# Generated by OpenFakeRAM
VERSION 5.7 ;
BUSBITCHARS "[]" ;
PROPERTYDEFINITIONS
  MACRO width INTEGER ;
  MACRO depth INTEGER ;
  MACRO banks INTEGER ;
END PROPERTYDEFINITIONS
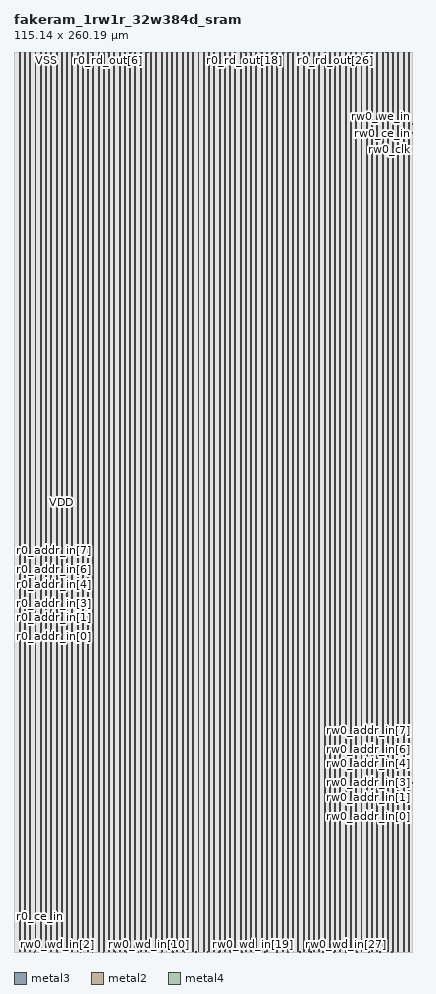
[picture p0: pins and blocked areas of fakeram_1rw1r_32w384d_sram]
MACRO fakeram_1rw1r_32w384d_sram
  PROPERTY width 32 ;
  PROPERTY depth 384 ;
  PROPERTY banks 1 ;
  FOREIGN fakeram_1rw1r_32w384d_sram 0 0 ;
  SYMMETRY X Y R90 ;
  SIZE 115.140 BY 260.190 ;
  CLASS BLOCK ;
  PIN r0_clk
    DIRECTION INPUT ;
    USE SIGNAL ;
    SHAPE ABUTMENT ;
    PORT
      LAYER metal3 ;
      RECT 0.000 7.945 0.070 8.015 ;
    END
  END r0_clk
  PIN r0_ce_in
    DIRECTION INPUT ;
    USE SIGNAL ;
    SHAPE ABUTMENT ;
    PORT
      LAYER metal3 ;
      RECT 0.000 10.325 0.070 10.395 ;
    END
  END r0_ce_in
  PIN r0_addr_in[0]
    DIRECTION INPUT ;
    USE SIGNAL ;
    SHAPE ABUTMENT ;
    PORT
      LAYER metal3 ;
      RECT 0.000 91.105 0.070 91.175 ;
    END
  END r0_addr_in[0]
  PIN r0_addr_in[1]
    DIRECTION INPUT ;
    USE SIGNAL ;
    SHAPE ABUTMENT ;
    PORT
      LAYER metal3 ;
      RECT 0.000 94.325 0.070 94.395 ;
    END
  END r0_addr_in[1]
  PIN r0_addr_in[2]
    DIRECTION INPUT ;
    USE SIGNAL ;
    SHAPE ABUTMENT ;
    PORT
      LAYER metal3 ;
      RECT 0.000 97.545 0.070 97.615 ;
    END
  END r0_addr_in[2]
  PIN r0_addr_in[3]
    DIRECTION INPUT ;
    USE SIGNAL ;
    SHAPE ABUTMENT ;
    PORT
      LAYER metal3 ;
      RECT 0.000 100.765 0.070 100.835 ;
    END
  END r0_addr_in[3]
  PIN r0_addr_in[4]
    DIRECTION INPUT ;
    USE SIGNAL ;
    SHAPE ABUTMENT ;
    PORT
      LAYER metal3 ;
      RECT 0.000 103.985 0.070 104.055 ;
    END
  END r0_addr_in[4]
  PIN r0_addr_in[5]
    DIRECTION INPUT ;
    USE SIGNAL ;
    SHAPE ABUTMENT ;
    PORT
      LAYER metal3 ;
      RECT 0.000 107.345 0.070 107.415 ;
    END
  END r0_addr_in[5]
  PIN r0_addr_in[6]
    DIRECTION INPUT ;
    USE SIGNAL ;
    SHAPE ABUTMENT ;
    PORT
      LAYER metal3 ;
      RECT 0.000 110.565 0.070 110.635 ;
    END
  END r0_addr_in[6]
  PIN r0_addr_in[7]
    DIRECTION INPUT ;
    USE SIGNAL ;
    SHAPE ABUTMENT ;
    PORT
      LAYER metal3 ;
      RECT 0.000 113.785 0.070 113.855 ;
    END
  END r0_addr_in[7]
  PIN r0_addr_in[8]
    DIRECTION INPUT ;
    USE SIGNAL ;
    SHAPE ABUTMENT ;
    PORT
      LAYER metal3 ;
      RECT 0.000 117.005 0.070 117.075 ;
    END
  END r0_addr_in[8]
  PIN rw0_rd_out[0]
    DIRECTION OUTPUT ;
    USE SIGNAL ;
    SHAPE ABUTMENT ;
    PORT
      LAYER metal2 ;
      RECT 5.855 260.120 5.925 260.190 ;
    END
  END rw0_rd_out[0]
  PIN r0_rd_out[0]
    DIRECTION OUTPUT ;
    USE SIGNAL ;
    SHAPE ABUTMENT ;
    PORT
      LAYER metal2 ;
      RECT 7.565 260.120 7.635 260.190 ;
    END
  END r0_rd_out[0]
  PIN rw0_rd_out[1]
    DIRECTION OUTPUT ;
    USE SIGNAL ;
    SHAPE ABUTMENT ;
    PORT
      LAYER metal2 ;
      RECT 9.085 260.120 9.155 260.190 ;
    END
  END rw0_rd_out[1]
  PIN r0_rd_out[1]
    DIRECTION OUTPUT ;
    USE SIGNAL ;
    SHAPE ABUTMENT ;
    PORT
      LAYER metal2 ;
      RECT 10.795 260.120 10.865 260.190 ;
    END
  END r0_rd_out[1]
  PIN rw0_rd_out[2]
    DIRECTION OUTPUT ;
    USE SIGNAL ;
    SHAPE ABUTMENT ;
    PORT
      LAYER metal2 ;
      RECT 12.505 260.120 12.575 260.190 ;
    END
  END rw0_rd_out[2]
  PIN r0_rd_out[2]
    DIRECTION OUTPUT ;
    USE SIGNAL ;
    SHAPE ABUTMENT ;
    PORT
      LAYER metal2 ;
      RECT 14.025 260.120 14.095 260.190 ;
    END
  END r0_rd_out[2]
  PIN rw0_rd_out[3]
    DIRECTION OUTPUT ;
    USE SIGNAL ;
    SHAPE ABUTMENT ;
    PORT
      LAYER metal2 ;
      RECT 15.735 260.120 15.805 260.190 ;
    END
  END rw0_rd_out[3]
  PIN r0_rd_out[3]
    DIRECTION OUTPUT ;
    USE SIGNAL ;
    SHAPE ABUTMENT ;
    PORT
      LAYER metal2 ;
      RECT 17.255 260.120 17.325 260.190 ;
    END
  END r0_rd_out[3]
  PIN rw0_rd_out[4]
    DIRECTION OUTPUT ;
    USE SIGNAL ;
    SHAPE ABUTMENT ;
    PORT
      LAYER metal2 ;
      RECT 18.965 260.120 19.035 260.190 ;
    END
  END rw0_rd_out[4]
  PIN r0_rd_out[4]
    DIRECTION OUTPUT ;
    USE SIGNAL ;
    SHAPE ABUTMENT ;
    PORT
      LAYER metal2 ;
      RECT 20.675 260.120 20.745 260.190 ;
    END
  END r0_rd_out[4]
  PIN rw0_rd_out[5]
    DIRECTION OUTPUT ;
    USE SIGNAL ;
    SHAPE ABUTMENT ;
    PORT
      LAYER metal2 ;
      RECT 22.195 260.120 22.265 260.190 ;
    END
  END rw0_rd_out[5]
  PIN r0_rd_out[5]
    DIRECTION OUTPUT ;
    USE SIGNAL ;
    SHAPE ABUTMENT ;
    PORT
      LAYER metal2 ;
      RECT 23.905 260.120 23.975 260.190 ;
    END
  END r0_rd_out[5]
  PIN rw0_rd_out[6]
    DIRECTION OUTPUT ;
    USE SIGNAL ;
    SHAPE ABUTMENT ;
    PORT
      LAYER metal2 ;
      RECT 25.615 260.120 25.685 260.190 ;
    END
  END rw0_rd_out[6]
  PIN r0_rd_out[6]
    DIRECTION OUTPUT ;
    USE SIGNAL ;
    SHAPE ABUTMENT ;
    PORT
      LAYER metal2 ;
      RECT 27.135 260.120 27.205 260.190 ;
    END
  END r0_rd_out[6]
  PIN rw0_rd_out[7]
    DIRECTION OUTPUT ;
    USE SIGNAL ;
    SHAPE ABUTMENT ;
    PORT
      LAYER metal2 ;
      RECT 28.845 260.120 28.915 260.190 ;
    END
  END rw0_rd_out[7]
  PIN r0_rd_out[7]
    DIRECTION OUTPUT ;
    USE SIGNAL ;
    SHAPE ABUTMENT ;
    PORT
      LAYER metal2 ;
      RECT 30.555 260.120 30.625 260.190 ;
    END
  END r0_rd_out[7]
  PIN rw0_rd_out[8]
    DIRECTION OUTPUT ;
    USE SIGNAL ;
    SHAPE ABUTMENT ;
    PORT
      LAYER metal2 ;
      RECT 32.075 260.120 32.145 260.190 ;
    END
  END rw0_rd_out[8]
  PIN r0_rd_out[8]
    DIRECTION OUTPUT ;
    USE SIGNAL ;
    SHAPE ABUTMENT ;
    PORT
      LAYER metal2 ;
      RECT 33.785 260.120 33.855 260.190 ;
    END
  END r0_rd_out[8]
  PIN rw0_rd_out[9]
    DIRECTION OUTPUT ;
    USE SIGNAL ;
    SHAPE ABUTMENT ;
    PORT
      LAYER metal2 ;
      RECT 35.305 260.120 35.375 260.190 ;
    END
  END rw0_rd_out[9]
  PIN r0_rd_out[9]
    DIRECTION OUTPUT ;
    USE SIGNAL ;
    SHAPE ABUTMENT ;
    PORT
      LAYER metal2 ;
      RECT 37.015 260.120 37.085 260.190 ;
    END
  END r0_rd_out[9]
  PIN rw0_rd_out[10]
    DIRECTION OUTPUT ;
    USE SIGNAL ;
    SHAPE ABUTMENT ;
    PORT
      LAYER metal2 ;
      RECT 38.725 260.120 38.795 260.190 ;
    END
  END rw0_rd_out[10]
  PIN r0_rd_out[10]
    DIRECTION OUTPUT ;
    USE SIGNAL ;
    SHAPE ABUTMENT ;
    PORT
      LAYER metal2 ;
      RECT 40.245 260.120 40.315 260.190 ;
    END
  END r0_rd_out[10]
  PIN rw0_rd_out[11]
    DIRECTION OUTPUT ;
    USE SIGNAL ;
    SHAPE ABUTMENT ;
    PORT
      LAYER metal2 ;
      RECT 41.955 260.120 42.025 260.190 ;
    END
  END rw0_rd_out[11]
  PIN r0_rd_out[11]
    DIRECTION OUTPUT ;
    USE SIGNAL ;
    SHAPE ABUTMENT ;
    PORT
      LAYER metal2 ;
      RECT 43.665 260.120 43.735 260.190 ;
    END
  END r0_rd_out[11]
  PIN rw0_rd_out[12]
    DIRECTION OUTPUT ;
    USE SIGNAL ;
    SHAPE ABUTMENT ;
    PORT
      LAYER metal2 ;
      RECT 45.185 260.120 45.255 260.190 ;
    END
  END rw0_rd_out[12]
  PIN r0_rd_out[12]
    DIRECTION OUTPUT ;
    USE SIGNAL ;
    SHAPE ABUTMENT ;
    PORT
      LAYER metal2 ;
      RECT 46.895 260.120 46.965 260.190 ;
    END
  END r0_rd_out[12]
  PIN rw0_rd_out[13]
    DIRECTION OUTPUT ;
    USE SIGNAL ;
    SHAPE ABUTMENT ;
    PORT
      LAYER metal2 ;
      RECT 48.605 260.120 48.675 260.190 ;
    END
  END rw0_rd_out[13]
  PIN r0_rd_out[13]
    DIRECTION OUTPUT ;
    USE SIGNAL ;
    SHAPE ABUTMENT ;
    PORT
      LAYER metal2 ;
      RECT 50.125 260.120 50.195 260.190 ;
    END
  END r0_rd_out[13]
  PIN rw0_rd_out[14]
    DIRECTION OUTPUT ;
    USE SIGNAL ;
    SHAPE ABUTMENT ;
    PORT
      LAYER metal2 ;
      RECT 51.835 260.120 51.905 260.190 ;
    END
  END rw0_rd_out[14]
  PIN r0_rd_out[14]
    DIRECTION OUTPUT ;
    USE SIGNAL ;
    SHAPE ABUTMENT ;
    PORT
      LAYER metal2 ;
      RECT 53.355 260.120 53.425 260.190 ;
    END
  END r0_rd_out[14]
  PIN rw0_rd_out[15]
    DIRECTION OUTPUT ;
    USE SIGNAL ;
    SHAPE ABUTMENT ;
    PORT
      LAYER metal2 ;
      RECT 55.065 260.120 55.135 260.190 ;
    END
  END rw0_rd_out[15]
  PIN r0_rd_out[15]
    DIRECTION OUTPUT ;
    USE SIGNAL ;
    SHAPE ABUTMENT ;
    PORT
      LAYER metal2 ;
      RECT 56.775 260.120 56.845 260.190 ;
    END
  END r0_rd_out[15]
  PIN rw0_rd_out[16]
    DIRECTION OUTPUT ;
    USE SIGNAL ;
    SHAPE ABUTMENT ;
    PORT
      LAYER metal2 ;
      RECT 58.295 260.120 58.365 260.190 ;
    END
  END rw0_rd_out[16]
  PIN r0_rd_out[16]
    DIRECTION OUTPUT ;
    USE SIGNAL ;
    SHAPE ABUTMENT ;
    PORT
      LAYER metal2 ;
      RECT 60.005 260.120 60.075 260.190 ;
    END
  END r0_rd_out[16]
  PIN rw0_rd_out[17]
    DIRECTION OUTPUT ;
    USE SIGNAL ;
    SHAPE ABUTMENT ;
    PORT
      LAYER metal2 ;
      RECT 61.715 260.120 61.785 260.190 ;
    END
  END rw0_rd_out[17]
  PIN r0_rd_out[17]
    DIRECTION OUTPUT ;
    USE SIGNAL ;
    SHAPE ABUTMENT ;
    PORT
      LAYER metal2 ;
      RECT 63.235 260.120 63.305 260.190 ;
    END
  END r0_rd_out[17]
  PIN rw0_rd_out[18]
    DIRECTION OUTPUT ;
    USE SIGNAL ;
    SHAPE ABUTMENT ;
    PORT
      LAYER metal2 ;
      RECT 64.945 260.120 65.015 260.190 ;
    END
  END rw0_rd_out[18]
  PIN r0_rd_out[18]
    DIRECTION OUTPUT ;
    USE SIGNAL ;
    SHAPE ABUTMENT ;
    PORT
      LAYER metal2 ;
      RECT 66.465 260.120 66.535 260.190 ;
    END
  END r0_rd_out[18]
  PIN rw0_rd_out[19]
    DIRECTION OUTPUT ;
    USE SIGNAL ;
    SHAPE ABUTMENT ;
    PORT
      LAYER metal2 ;
      RECT 68.175 260.120 68.245 260.190 ;
    END
  END rw0_rd_out[19]
  PIN r0_rd_out[19]
    DIRECTION OUTPUT ;
    USE SIGNAL ;
    SHAPE ABUTMENT ;
    PORT
      LAYER metal2 ;
      RECT 69.885 260.120 69.955 260.190 ;
    END
  END r0_rd_out[19]
  PIN rw0_rd_out[20]
    DIRECTION OUTPUT ;
    USE SIGNAL ;
    SHAPE ABUTMENT ;
    PORT
      LAYER metal2 ;
      RECT 71.405 260.120 71.475 260.190 ;
    END
  END rw0_rd_out[20]
  PIN r0_rd_out[20]
    DIRECTION OUTPUT ;
    USE SIGNAL ;
    SHAPE ABUTMENT ;
    PORT
      LAYER metal2 ;
      RECT 73.115 260.120 73.185 260.190 ;
    END
  END r0_rd_out[20]
  PIN rw0_rd_out[21]
    DIRECTION OUTPUT ;
    USE SIGNAL ;
    SHAPE ABUTMENT ;
    PORT
      LAYER metal2 ;
      RECT 74.825 260.120 74.895 260.190 ;
    END
  END rw0_rd_out[21]
  PIN r0_rd_out[21]
    DIRECTION OUTPUT ;
    USE SIGNAL ;
    SHAPE ABUTMENT ;
    PORT
      LAYER metal2 ;
      RECT 76.345 260.120 76.415 260.190 ;
    END
  END r0_rd_out[21]
  PIN rw0_rd_out[22]
    DIRECTION OUTPUT ;
    USE SIGNAL ;
    SHAPE ABUTMENT ;
    PORT
      LAYER metal2 ;
      RECT 78.055 260.120 78.125 260.190 ;
    END
  END rw0_rd_out[22]
  PIN r0_rd_out[22]
    DIRECTION OUTPUT ;
    USE SIGNAL ;
    SHAPE ABUTMENT ;
    PORT
      LAYER metal2 ;
      RECT 79.765 260.120 79.835 260.190 ;
    END
  END r0_rd_out[22]
  PIN rw0_rd_out[23]
    DIRECTION OUTPUT ;
    USE SIGNAL ;
    SHAPE ABUTMENT ;
    PORT
      LAYER metal2 ;
      RECT 81.285 260.120 81.355 260.190 ;
    END
  END rw0_rd_out[23]
  PIN r0_rd_out[23]
    DIRECTION OUTPUT ;
    USE SIGNAL ;
    SHAPE ABUTMENT ;
    PORT
      LAYER metal2 ;
      RECT 82.995 260.120 83.065 260.190 ;
    END
  END r0_rd_out[23]
  PIN rw0_rd_out[24]
    DIRECTION OUTPUT ;
    USE SIGNAL ;
    SHAPE ABUTMENT ;
    PORT
      LAYER metal2 ;
      RECT 84.515 260.120 84.585 260.190 ;
    END
  END rw0_rd_out[24]
  PIN r0_rd_out[24]
    DIRECTION OUTPUT ;
    USE SIGNAL ;
    SHAPE ABUTMENT ;
    PORT
      LAYER metal2 ;
      RECT 86.225 260.120 86.295 260.190 ;
    END
  END r0_rd_out[24]
  PIN rw0_rd_out[25]
    DIRECTION OUTPUT ;
    USE SIGNAL ;
    SHAPE ABUTMENT ;
    PORT
      LAYER metal2 ;
      RECT 87.935 260.120 88.005 260.190 ;
    END
  END rw0_rd_out[25]
  PIN r0_rd_out[25]
    DIRECTION OUTPUT ;
    USE SIGNAL ;
    SHAPE ABUTMENT ;
    PORT
      LAYER metal2 ;
      RECT 89.455 260.120 89.525 260.190 ;
    END
  END r0_rd_out[25]
  PIN rw0_rd_out[26]
    DIRECTION OUTPUT ;
    USE SIGNAL ;
    SHAPE ABUTMENT ;
    PORT
      LAYER metal2 ;
      RECT 91.165 260.120 91.235 260.190 ;
    END
  END rw0_rd_out[26]
  PIN r0_rd_out[26]
    DIRECTION OUTPUT ;
    USE SIGNAL ;
    SHAPE ABUTMENT ;
    PORT
      LAYER metal2 ;
      RECT 92.875 260.120 92.945 260.190 ;
    END
  END r0_rd_out[26]
  PIN rw0_rd_out[27]
    DIRECTION OUTPUT ;
    USE SIGNAL ;
    SHAPE ABUTMENT ;
    PORT
      LAYER metal2 ;
      RECT 94.395 260.120 94.465 260.190 ;
    END
  END rw0_rd_out[27]
  PIN r0_rd_out[27]
    DIRECTION OUTPUT ;
    USE SIGNAL ;
    SHAPE ABUTMENT ;
    PORT
      LAYER metal2 ;
      RECT 96.105 260.120 96.175 260.190 ;
    END
  END r0_rd_out[27]
  PIN rw0_rd_out[28]
    DIRECTION OUTPUT ;
    USE SIGNAL ;
    SHAPE ABUTMENT ;
    PORT
      LAYER metal2 ;
      RECT 97.815 260.120 97.885 260.190 ;
    END
  END rw0_rd_out[28]
  PIN r0_rd_out[28]
    DIRECTION OUTPUT ;
    USE SIGNAL ;
    SHAPE ABUTMENT ;
    PORT
      LAYER metal2 ;
      RECT 99.335 260.120 99.405 260.190 ;
    END
  END r0_rd_out[28]
  PIN rw0_rd_out[29]
    DIRECTION OUTPUT ;
    USE SIGNAL ;
    SHAPE ABUTMENT ;
    PORT
      LAYER metal2 ;
      RECT 101.045 260.120 101.115 260.190 ;
    END
  END rw0_rd_out[29]
  PIN r0_rd_out[29]
    DIRECTION OUTPUT ;
    USE SIGNAL ;
    SHAPE ABUTMENT ;
    PORT
      LAYER metal2 ;
      RECT 102.565 260.120 102.635 260.190 ;
    END
  END r0_rd_out[29]
  PIN rw0_rd_out[30]
    DIRECTION OUTPUT ;
    USE SIGNAL ;
    SHAPE ABUTMENT ;
    PORT
      LAYER metal2 ;
      RECT 104.275 260.120 104.345 260.190 ;
    END
  END rw0_rd_out[30]
  PIN r0_rd_out[30]
    DIRECTION OUTPUT ;
    USE SIGNAL ;
    SHAPE ABUTMENT ;
    PORT
      LAYER metal2 ;
      RECT 105.985 260.120 106.055 260.190 ;
    END
  END r0_rd_out[30]
  PIN rw0_rd_out[31]
    DIRECTION OUTPUT ;
    USE SIGNAL ;
    SHAPE ABUTMENT ;
    PORT
      LAYER metal2 ;
      RECT 107.505 260.120 107.575 260.190 ;
    END
  END rw0_rd_out[31]
  PIN r0_rd_out[31]
    DIRECTION OUTPUT ;
    USE SIGNAL ;
    SHAPE ABUTMENT ;
    PORT
      LAYER metal2 ;
      RECT 109.215 260.120 109.285 260.190 ;
    END
  END r0_rd_out[31]
  PIN rw0_clk
    DIRECTION INPUT ;
    USE SIGNAL ;
    SHAPE ABUTMENT ;
    PORT
      LAYER metal3 ;
      RECT 115.070 234.185 115.140 234.255 ;
    END
  END rw0_clk
  PIN rw0_ce_in
    DIRECTION INPUT ;
    USE SIGNAL ;
    SHAPE ABUTMENT ;
    PORT
      LAYER metal3 ;
      RECT 115.070 236.705 115.140 236.775 ;
    END
  END rw0_ce_in
  PIN rw0_we_in
    DIRECTION INPUT ;
    USE SIGNAL ;
    SHAPE ABUTMENT ;
    PORT
      LAYER metal3 ;
      RECT 115.070 239.365 115.140 239.435 ;
    END
  END rw0_we_in
  PIN rw0_addr_in[0]
    DIRECTION INPUT ;
    USE SIGNAL ;
    SHAPE ABUTMENT ;
    PORT
      LAYER metal3 ;
      RECT 115.070 39.165 115.140 39.235 ;
    END
  END rw0_addr_in[0]
  PIN rw0_addr_in[1]
    DIRECTION INPUT ;
    USE SIGNAL ;
    SHAPE ABUTMENT ;
    PORT
      LAYER metal3 ;
      RECT 115.070 42.385 115.140 42.455 ;
    END
  END rw0_addr_in[1]
  PIN rw0_addr_in[2]
    DIRECTION INPUT ;
    USE SIGNAL ;
    SHAPE ABUTMENT ;
    PORT
      LAYER metal3 ;
      RECT 115.070 45.605 115.140 45.675 ;
    END
  END rw0_addr_in[2]
  PIN rw0_addr_in[3]
    DIRECTION INPUT ;
    USE SIGNAL ;
    SHAPE ABUTMENT ;
    PORT
      LAYER metal3 ;
      RECT 115.070 48.825 115.140 48.895 ;
    END
  END rw0_addr_in[3]
  PIN rw0_addr_in[4]
    DIRECTION INPUT ;
    USE SIGNAL ;
    SHAPE ABUTMENT ;
    PORT
      LAYER metal3 ;
      RECT 115.070 52.045 115.140 52.115 ;
    END
  END rw0_addr_in[4]
  PIN rw0_addr_in[5]
    DIRECTION INPUT ;
    USE SIGNAL ;
    SHAPE ABUTMENT ;
    PORT
      LAYER metal3 ;
      RECT 115.070 55.265 115.140 55.335 ;
    END
  END rw0_addr_in[5]
  PIN rw0_addr_in[6]
    DIRECTION INPUT ;
    USE SIGNAL ;
    SHAPE ABUTMENT ;
    PORT
      LAYER metal3 ;
      RECT 115.070 58.485 115.140 58.555 ;
    END
  END rw0_addr_in[6]
  PIN rw0_addr_in[7]
    DIRECTION INPUT ;
    USE SIGNAL ;
    SHAPE ABUTMENT ;
    PORT
      LAYER metal3 ;
      RECT 115.070 61.705 115.140 61.775 ;
    END
  END rw0_addr_in[7]
  PIN rw0_addr_in[8]
    DIRECTION INPUT ;
    USE SIGNAL ;
    SHAPE ABUTMENT ;
    PORT
      LAYER metal3 ;
      RECT 115.070 64.925 115.140 64.995 ;
    END
  END rw0_addr_in[8]
  PIN rw0_wd_in[0]
    DIRECTION INPUT ;
    USE SIGNAL ;
    SHAPE ABUTMENT ;
    PORT
      LAYER metal2 ;
      RECT 5.855 0.000 5.925 0.070 ;
    END
  END rw0_wd_in[0]
  PIN rw0_wd_in[1]
    DIRECTION INPUT ;
    USE SIGNAL ;
    SHAPE ABUTMENT ;
    PORT
      LAYER metal2 ;
      RECT 9.275 0.000 9.345 0.070 ;
    END
  END rw0_wd_in[1]
  PIN rw0_wd_in[2]
    DIRECTION INPUT ;
    USE SIGNAL ;
    SHAPE ABUTMENT ;
    PORT
      LAYER metal2 ;
      RECT 12.505 0.000 12.575 0.070 ;
    END
  END rw0_wd_in[2]
  PIN rw0_wd_in[3]
    DIRECTION INPUT ;
    USE SIGNAL ;
    SHAPE ABUTMENT ;
    PORT
      LAYER metal2 ;
      RECT 15.925 0.000 15.995 0.070 ;
    END
  END rw0_wd_in[3]
  PIN rw0_wd_in[4]
    DIRECTION INPUT ;
    USE SIGNAL ;
    SHAPE ABUTMENT ;
    PORT
      LAYER metal2 ;
      RECT 19.155 0.000 19.225 0.070 ;
    END
  END rw0_wd_in[4]
  PIN rw0_wd_in[5]
    DIRECTION INPUT ;
    USE SIGNAL ;
    SHAPE ABUTMENT ;
    PORT
      LAYER metal2 ;
      RECT 22.575 0.000 22.645 0.070 ;
    END
  END rw0_wd_in[5]
  PIN rw0_wd_in[6]
    DIRECTION INPUT ;
    USE SIGNAL ;
    SHAPE ABUTMENT ;
    PORT
      LAYER metal2 ;
      RECT 25.805 0.000 25.875 0.070 ;
    END
  END rw0_wd_in[6]
  PIN rw0_wd_in[7]
    DIRECTION INPUT ;
    USE SIGNAL ;
    SHAPE ABUTMENT ;
    PORT
      LAYER metal2 ;
      RECT 29.225 0.000 29.295 0.070 ;
    END
  END rw0_wd_in[7]
  PIN rw0_wd_in[8]
    DIRECTION INPUT ;
    USE SIGNAL ;
    SHAPE ABUTMENT ;
    PORT
      LAYER metal2 ;
      RECT 32.455 0.000 32.525 0.070 ;
    END
  END rw0_wd_in[8]
  PIN rw0_wd_in[9]
    DIRECTION INPUT ;
    USE SIGNAL ;
    SHAPE ABUTMENT ;
    PORT
      LAYER metal2 ;
      RECT 35.875 0.000 35.945 0.070 ;
    END
  END rw0_wd_in[9]
  PIN rw0_wd_in[10]
    DIRECTION INPUT ;
    USE SIGNAL ;
    SHAPE ABUTMENT ;
    PORT
      LAYER metal2 ;
      RECT 39.105 0.000 39.175 0.070 ;
    END
  END rw0_wd_in[10]
  PIN rw0_wd_in[11]
    DIRECTION INPUT ;
    USE SIGNAL ;
    SHAPE ABUTMENT ;
    PORT
      LAYER metal2 ;
      RECT 42.525 0.000 42.595 0.070 ;
    END
  END rw0_wd_in[11]
  PIN rw0_wd_in[12]
    DIRECTION INPUT ;
    USE SIGNAL ;
    SHAPE ABUTMENT ;
    PORT
      LAYER metal2 ;
      RECT 45.945 0.000 46.015 0.070 ;
    END
  END rw0_wd_in[12]
  PIN rw0_wd_in[13]
    DIRECTION INPUT ;
    USE SIGNAL ;
    SHAPE ABUTMENT ;
    PORT
      LAYER metal2 ;
      RECT 49.175 0.000 49.245 0.070 ;
    END
  END rw0_wd_in[13]
  PIN rw0_wd_in[14]
    DIRECTION INPUT ;
    USE SIGNAL ;
    SHAPE ABUTMENT ;
    PORT
      LAYER metal2 ;
      RECT 52.595 0.000 52.665 0.070 ;
    END
  END rw0_wd_in[14]
  PIN rw0_wd_in[15]
    DIRECTION INPUT ;
    USE SIGNAL ;
    SHAPE ABUTMENT ;
    PORT
      LAYER metal2 ;
      RECT 55.825 0.000 55.895 0.070 ;
    END
  END rw0_wd_in[15]
  PIN rw0_wd_in[16]
    DIRECTION INPUT ;
    USE SIGNAL ;
    SHAPE ABUTMENT ;
    PORT
      LAYER metal2 ;
      RECT 59.245 0.000 59.315 0.070 ;
    END
  END rw0_wd_in[16]
  PIN rw0_wd_in[17]
    DIRECTION INPUT ;
    USE SIGNAL ;
    SHAPE ABUTMENT ;
    PORT
      LAYER metal2 ;
      RECT 62.475 0.000 62.545 0.070 ;
    END
  END rw0_wd_in[17]
  PIN rw0_wd_in[18]
    DIRECTION INPUT ;
    USE SIGNAL ;
    SHAPE ABUTMENT ;
    PORT
      LAYER metal2 ;
      RECT 65.895 0.000 65.965 0.070 ;
    END
  END rw0_wd_in[18]
  PIN rw0_wd_in[19]
    DIRECTION INPUT ;
    USE SIGNAL ;
    SHAPE ABUTMENT ;
    PORT
      LAYER metal2 ;
      RECT 69.125 0.000 69.195 0.070 ;
    END
  END rw0_wd_in[19]
  PIN rw0_wd_in[20]
    DIRECTION INPUT ;
    USE SIGNAL ;
    SHAPE ABUTMENT ;
    PORT
      LAYER metal2 ;
      RECT 72.545 0.000 72.615 0.070 ;
    END
  END rw0_wd_in[20]
  PIN rw0_wd_in[21]
    DIRECTION INPUT ;
    USE SIGNAL ;
    SHAPE ABUTMENT ;
    PORT
      LAYER metal2 ;
      RECT 75.965 0.000 76.035 0.070 ;
    END
  END rw0_wd_in[21]
  PIN rw0_wd_in[22]
    DIRECTION INPUT ;
    USE SIGNAL ;
    SHAPE ABUTMENT ;
    PORT
      LAYER metal2 ;
      RECT 79.195 0.000 79.265 0.070 ;
    END
  END rw0_wd_in[22]
  PIN rw0_wd_in[23]
    DIRECTION INPUT ;
    USE SIGNAL ;
    SHAPE ABUTMENT ;
    PORT
      LAYER metal2 ;
      RECT 82.615 0.000 82.685 0.070 ;
    END
  END rw0_wd_in[23]
  PIN rw0_wd_in[24]
    DIRECTION INPUT ;
    USE SIGNAL ;
    SHAPE ABUTMENT ;
    PORT
      LAYER metal2 ;
      RECT 85.845 0.000 85.915 0.070 ;
    END
  END rw0_wd_in[24]
  PIN rw0_wd_in[25]
    DIRECTION INPUT ;
    USE SIGNAL ;
    SHAPE ABUTMENT ;
    PORT
      LAYER metal2 ;
      RECT 89.265 0.000 89.335 0.070 ;
    END
  END rw0_wd_in[25]
  PIN rw0_wd_in[26]
    DIRECTION INPUT ;
    USE SIGNAL ;
    SHAPE ABUTMENT ;
    PORT
      LAYER metal2 ;
      RECT 92.495 0.000 92.565 0.070 ;
    END
  END rw0_wd_in[26]
  PIN rw0_wd_in[27]
    DIRECTION INPUT ;
    USE SIGNAL ;
    SHAPE ABUTMENT ;
    PORT
      LAYER metal2 ;
      RECT 95.915 0.000 95.985 0.070 ;
    END
  END rw0_wd_in[27]
  PIN rw0_wd_in[28]
    DIRECTION INPUT ;
    USE SIGNAL ;
    SHAPE ABUTMENT ;
    PORT
      LAYER metal2 ;
      RECT 99.145 0.000 99.215 0.070 ;
    END
  END rw0_wd_in[28]
  PIN rw0_wd_in[29]
    DIRECTION INPUT ;
    USE SIGNAL ;
    SHAPE ABUTMENT ;
    PORT
      LAYER metal2 ;
      RECT 102.565 0.000 102.635 0.070 ;
    END
  END rw0_wd_in[29]
  PIN rw0_wd_in[30]
    DIRECTION INPUT ;
    USE SIGNAL ;
    SHAPE ABUTMENT ;
    PORT
      LAYER metal2 ;
      RECT 105.795 0.000 105.865 0.070 ;
    END
  END rw0_wd_in[30]
  PIN rw0_wd_in[31]
    DIRECTION INPUT ;
    USE SIGNAL ;
    SHAPE ABUTMENT ;
    PORT
      LAYER metal2 ;
      RECT 109.215 0.000 109.285 0.070 ;
    END
  END rw0_wd_in[31]
  PIN VSS
    DIRECTION INOUT ;
    USE GROUND ;
    PORT
      LAYER metal4 ;
      RECT 3.040 0.140 3.320 260.050 ;
      RECT 6.080 0.140 6.360 260.050 ;
      RECT 9.120 0.140 9.400 260.050 ;
      RECT 12.160 0.140 12.440 260.050 ;
      RECT 15.200 0.140 15.480 260.050 ;
      RECT 18.240 0.140 18.520 260.050 ;
      RECT 21.280 0.140 21.560 260.050 ;
      RECT 24.320 0.140 24.600 260.050 ;
      RECT 27.360 0.140 27.640 260.050 ;
      RECT 30.400 0.140 30.680 260.050 ;
      RECT 33.440 0.140 33.720 260.050 ;
      RECT 36.480 0.140 36.760 260.050 ;
      RECT 39.520 0.140 39.800 260.050 ;
      RECT 42.560 0.140 42.840 260.050 ;
      RECT 45.600 0.140 45.880 260.050 ;
      RECT 48.640 0.140 48.920 260.050 ;
      RECT 51.680 0.140 51.960 260.050 ;
      RECT 54.720 0.140 55.000 260.050 ;
      RECT 57.760 0.140 58.040 260.050 ;
      RECT 60.800 0.140 61.080 260.050 ;
      RECT 63.840 0.140 64.120 260.050 ;
      RECT 66.880 0.140 67.160 260.050 ;
      RECT 69.920 0.140 70.200 260.050 ;
      RECT 72.960 0.140 73.240 260.050 ;
      RECT 76.000 0.140 76.280 260.050 ;
      RECT 79.040 0.140 79.320 260.050 ;
      RECT 82.080 0.140 82.360 260.050 ;
      RECT 85.120 0.140 85.400 260.050 ;
      RECT 88.160 0.140 88.440 260.050 ;
      RECT 91.200 0.140 91.480 260.050 ;
      RECT 94.240 0.140 94.520 260.050 ;
      RECT 97.280 0.140 97.560 260.050 ;
      RECT 100.320 0.140 100.600 260.050 ;
      RECT 103.360 0.140 103.640 260.050 ;
      RECT 106.400 0.140 106.680 260.050 ;
      RECT 109.440 0.140 109.720 260.050 ;
      RECT 112.480 0.140 112.760 260.050 ;
    END
  END VSS
  PIN VDD
    DIRECTION INOUT ;
    USE POWER ;
    PORT
      LAYER metal4 ;
      RECT 1.520 0.140 1.800 260.050 ;
      RECT 4.560 0.140 4.840 260.050 ;
      RECT 7.600 0.140 7.880 260.050 ;
      RECT 10.640 0.140 10.920 260.050 ;
      RECT 13.680 0.140 13.960 260.050 ;
      RECT 16.720 0.140 17.000 260.050 ;
      RECT 19.760 0.140 20.040 260.050 ;
      RECT 22.800 0.140 23.080 260.050 ;
      RECT 25.840 0.140 26.120 260.050 ;
      RECT 28.880 0.140 29.160 260.050 ;
      RECT 31.920 0.140 32.200 260.050 ;
      RECT 34.960 0.140 35.240 260.050 ;
      RECT 38.000 0.140 38.280 260.050 ;
      RECT 41.040 0.140 41.320 260.050 ;
      RECT 44.080 0.140 44.360 260.050 ;
      RECT 47.120 0.140 47.400 260.050 ;
      RECT 50.160 0.140 50.440 260.050 ;
      RECT 53.200 0.140 53.480 260.050 ;
      RECT 56.240 0.140 56.520 260.050 ;
      RECT 59.280 0.140 59.560 260.050 ;
      RECT 62.320 0.140 62.600 260.050 ;
      RECT 65.360 0.140 65.640 260.050 ;
      RECT 68.400 0.140 68.680 260.050 ;
      RECT 71.440 0.140 71.720 260.050 ;
      RECT 74.480 0.140 74.760 260.050 ;
      RECT 77.520 0.140 77.800 260.050 ;
      RECT 80.560 0.140 80.840 260.050 ;
      RECT 83.600 0.140 83.880 260.050 ;
      RECT 86.640 0.140 86.920 260.050 ;
      RECT 89.680 0.140 89.960 260.050 ;
      RECT 92.720 0.140 93.000 260.050 ;
      RECT 95.760 0.140 96.040 260.050 ;
      RECT 98.800 0.140 99.080 260.050 ;
      RECT 101.840 0.140 102.120 260.050 ;
      RECT 104.880 0.140 105.160 260.050 ;
      RECT 107.920 0.140 108.200 260.050 ;
      RECT 110.960 0.140 111.240 260.050 ;
      RECT 114.000 0.140 114.280 260.050 ;
    END
  END VDD
  OBS
    LAYER metal1 ;
    RECT 0 0 115.140 260.190 ;
    LAYER metal2 ;
    RECT 0 0 115.140 260.190 ;
    LAYER metal3 ;
    RECT 0 0 115.140 260.190 ;
    LAYER metal4 ;
    RECT 0 0 115.140 260.190 ;
    LAYER OVERLAP ;
    RECT 0 0 115.140 260.190 ;
  END
END fakeram_1rw1r_32w384d_sram

END LIBRARY
